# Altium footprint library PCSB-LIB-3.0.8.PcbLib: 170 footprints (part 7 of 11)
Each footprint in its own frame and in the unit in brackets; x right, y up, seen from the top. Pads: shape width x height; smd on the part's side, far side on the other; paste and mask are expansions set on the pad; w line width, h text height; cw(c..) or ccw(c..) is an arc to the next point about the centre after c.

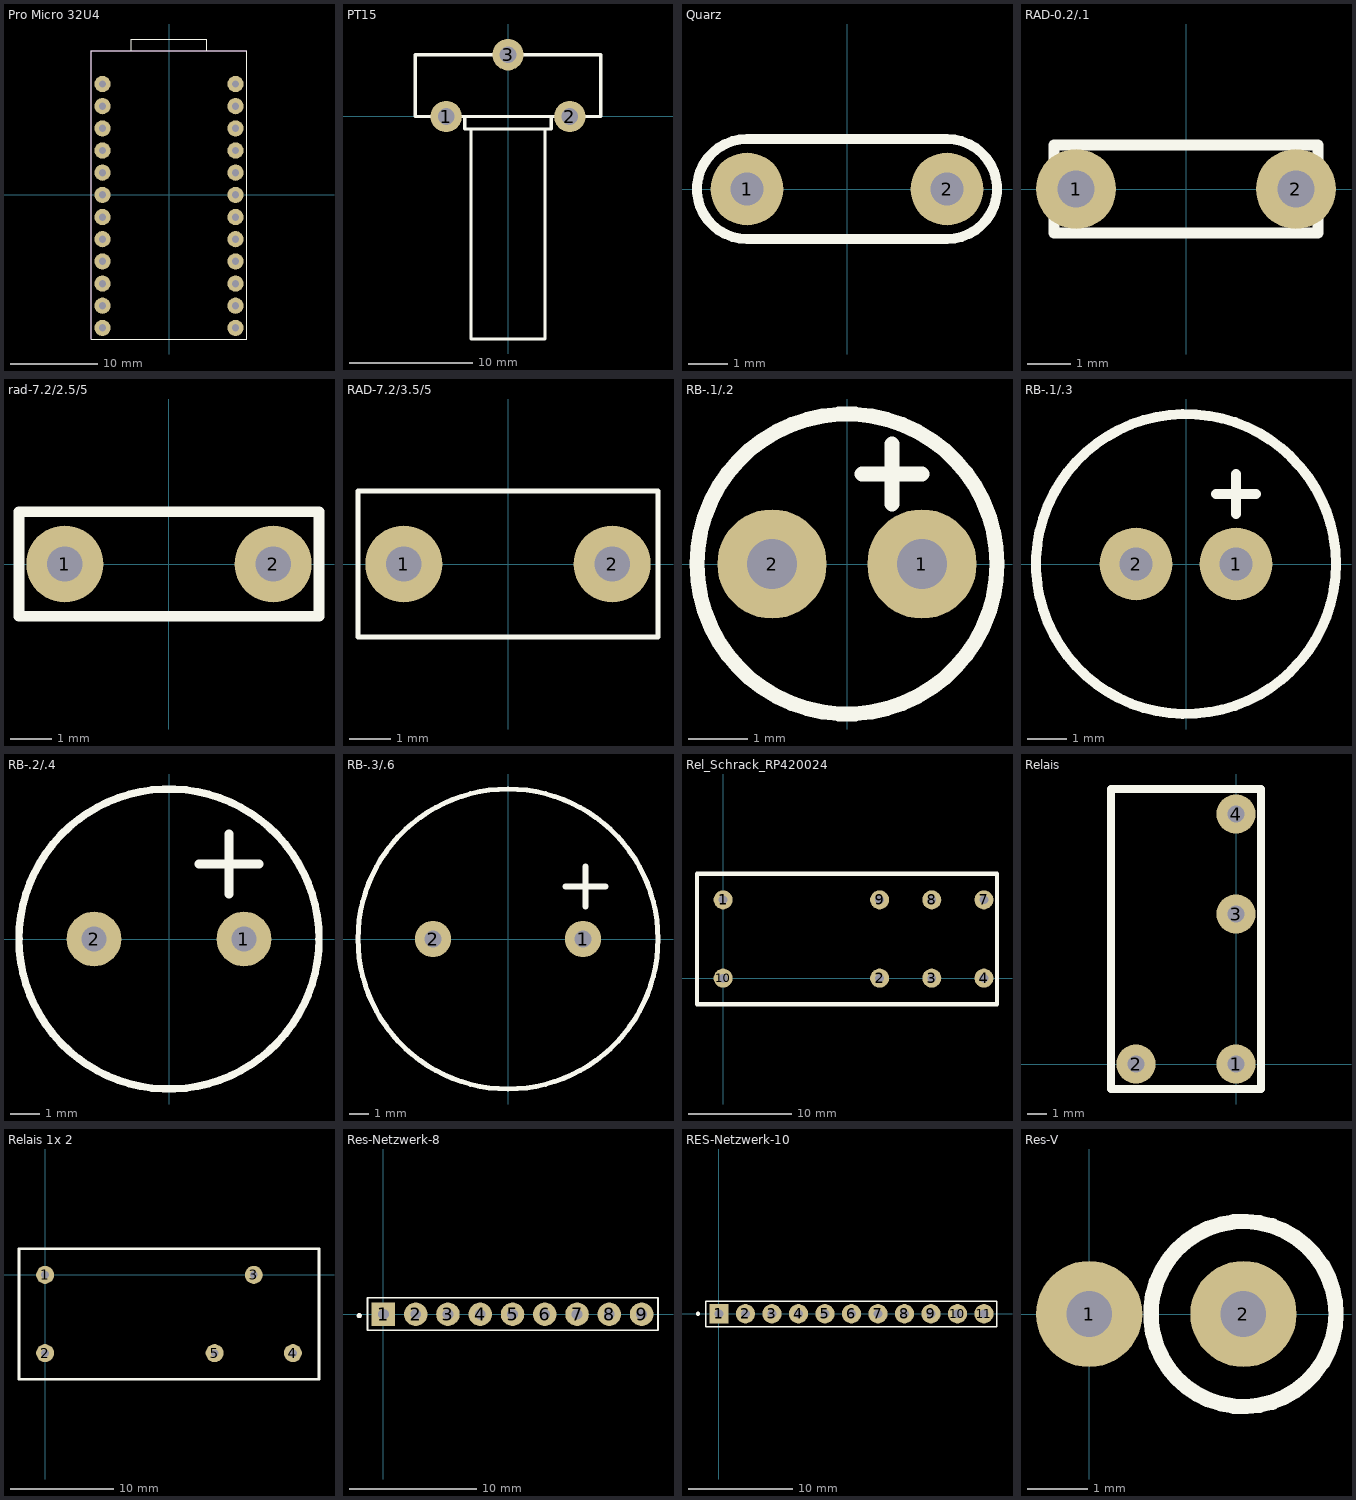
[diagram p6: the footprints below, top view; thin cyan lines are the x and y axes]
## Pro Micro 32U4 [mm]
pads (24):
  round 1.85 hole 0.85 mask+0.05: J3_1(-7.62,-15.24) J3_2(-7.62,-12.7) J3_3(-7.62,-10.16) J3_4(-7.62,-7.62) J3_5(-7.62,-5.08) J3_6(-7.62,-2.54) J3_7(-7.62,0) J3_8(-7.62,2.54) J3_9(-7.62,5.08) J3_10(-7.62,7.62) J3_11(-7.62,10.16) J3_12(-7.62,12.7) J4_1(7.62,12.7) J4_2(7.62,10.16) J4_3(7.62,7.62) J4_4(7.62,5.08) J4_5(7.62,2.54) J4_6(7.62,0) J4_7(7.62,-2.54) J4_8(7.62,-5.08) J4_9(7.62,-7.62) J4_10(7.62,-10.16) J4_11(7.62,-12.7) J4_12(7.62,-15.24)
Top Overlay:
  lines w0.127: -4.32,16.51 -4.32,17.855 4.32,17.855 4.32,16.51 ; -8.89,-16.51 -8.89,16.51 8.89,16.51 8.89,-16.51 -8.89,-16.51
Mechanical 13:
  lines w0.127: -8.89,-16.51 -8.89,16.51 -4.32,16.51 4.32,16.51 8.89,16.51 8.89,-16.51 -8.89,-16.51

## PT15 [mm]
pads (3):
  round 2.54 hole 1.35: 1(-5.006,-0.011) 2(4.994,-0.011) 3(-0.006,4.989)
Top Overlay:
  lines w0.254: -3.506,-0.011 -3.506,-1.011 3.494,-1.011 3.494,-0.011 ; -3,-1.011 -3,-18 3,-18 3,-1.011 ; -7.506,-0.011 -7.506,4.989 7.494,4.989 7.494,-0.011 -7.506,-0.011

## Quarz [mm]
pads (2):
  round 1.85 hole 0.85: 1(-2.54,0) 2(2.54,0)
Top Overlay:
  lines w0.254: -2.54,-1.27 cw(c-2.54,0) -2.54,1.27 2.54,1.27 cw(c2.54,0) 2.54,-1.27 -2.54,-1.27

## RAD-0.2/.1 [mm]
pads (2):
  round 1.85 hole 0.85: 1(-2.54,0) 2(2.54,0)
Top Overlay:
  lines w0.254: -3.048,-1.016 3.048,-1.016 3.048,1.016 -3.048,1.016 -3.048,-1.016

## rad-7.2/2.5/5 [mm]
pads (2):
  round 1.85 hole 0.85: 1(-2.5,0) 2(2.5,0)
Top Overlay:
  lines w0.254: -3.6,-1.25 3.6,-1.25 3.6,1.25 -3.6,1.25 -3.6,-1.25

## RAD-7.2/3.5/5 [mm]
pads (2):
  round 1.85 hole 0.85: 1(-2.5,0) 2(2.5,0)
Top Overlay:
  lines w0.127: -3.6,-1.75 3.6,-1.75 3.6,1.75 -3.6,1.75 -3.6,-1.75

## RB-.1/.2 [mm]
pads (2):
  round 1.85 hole 0.85: 1(1.27,0) 2(-1.27,0)
Top Overlay:
  circle w0.254: c0,0 r2.54
  lines w0.254: 0.254,1.524 1.27,1.524 ; 0.762,1.016 0.762,2.032

## RB-.1/.3 [mm]
pads (2):
  round 1.85 hole 0.85: 1(1.27,0) 2(-1.27,0)
Top Overlay:
  circle w0.254: c0,0 r3.81
  lines w0.254: 0.762,1.778 1.778,1.778 ; 1.27,1.27 1.27,2.286

## RB-.2/.4 [mm]
pads (2):
  round 1.85 hole 0.85: 1(2.54,0) 2(-2.54,0)
Top Overlay:
  circle w0.254: c0,0 r5.08
  lines w0.305: 1.016,2.54 3.048,2.54 ; 2.032,1.524 2.032,3.556

## RB-.3/.6 [mm]
pads (2):
  round 1.85 hole 0.85: 1(3.81,0) 2(-3.81,0)
Top Overlay:
  circle w0.254: c0,0 r7.62
  lines w0.305: 2.921,2.667 3.429,2.667 4.445,2.667 4.953,2.667 ; 3.937,1.651 3.937,2.159 3.937,3.175 3.937,3.683

## Rel_Schrack_RP420024 [mm] "24V; 2 Wechselkontakte 250V/8A"
height 25
pads (8):
  round 1.85 hole 0.85: 1(0,7.62) 2(15.24,0) 3(20.32,0) 4(25.4,0) 7(25.4,7.62) 8(20.32,7.62) 9(15.24,7.62) 10(0,0)
Top Overlay:
  lines w0.4: -2.54,-2.54 26.67,-2.54 26.67,10.16 25.4,10.16 -2.54,10.16 -2.54,-2.54

## Relais [mm] "K?"
pads (4):
  round 2 hole 0.85: 1(0,0) 2(-5.08,0) 3(0,7.62) 4(0,12.7)
Top Overlay:
  lines w0.4: -6.35,-1.27 -6.35,13.97 1.27,13.97 1.27,-1.27 -6.35,-1.27

## Relais 1x 2 [mm]
pads (5):
  round 1.75 hole 0.75: 1(0,0) 2(0,-7.62) 3(20.32,0) 4(24.13,-7.62) 5(16.51,-7.62)
Top Overlay:
  lines w0.254: -2.54,-10.16 -2.54,2.54 26.67,2.54 26.67,-10.16 -2.54,-10.16

## Res-Netzwerk-8 [mm]
height 5.08
pads (9):
  rect 1.85x1.85 hole 0.85: 1(0,0)
  round 1.85 hole 0.85: 2(2.54,0) 3(5.08,0) 4(7.62,0) 5(10.16,0) 6(12.7,0) 7(15.24,0) 8(17.78,0) 9(20.32,0)
Top Overlay:
  circle w0.2: c-1.9,-0.1 r0.1
  lines w0.127: -1.25,-1.25 -1.25,1.3 21.61,1.3 21.61,-1.25 -1.25,-1.25

## RES-Netzwerk-10 [mm]
height 5.08
pads (11):
  rect 1.85x1.85 hole 0.85: 1(0,0)
  round 1.85 hole 0.85: 2(2.54,0) 3(5.08,0) 4(7.62,0) 5(10.16,0) 6(12.7,0) 7(15.24,0) 8(17.78,0) 9(20.32,0) 10(22.86,0) 11(25.4,0)
Top Overlay:
  circle w0.2: c-2,0 r0.1
  lines w0.127: -1.25,-1.25 26.65,-1.25 26.65,1.2 -1.25,1.2 -1.25,-1.25

## Res-V [mm]
pads (2):
  round 1.75 hole 0.75: 1(0,0) 2(2.54,0)
Top Overlay:
  circle w0.254: c2.54,0 r1.524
